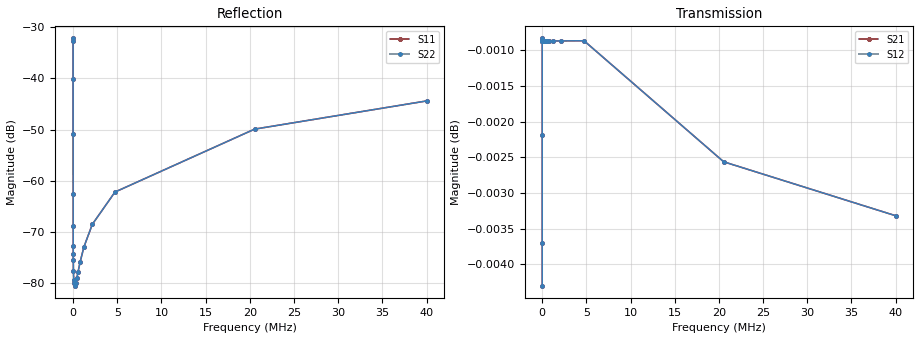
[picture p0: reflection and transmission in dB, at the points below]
!  *** S-Parameter ***
!  Copyright (C) Panasonic Industry
!  Conductive Polymer Aluminum Solid Capacitors (OS-CON)
!  Parts No. 2R5SVT680MX
! Touchstone file from project
# GHZ S RI R 50.000000
! Modal data exported
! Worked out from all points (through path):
!   450 points, 100 Hz to 40 MHz, reference 50 ohm
!   highest |S21| = 0.00 dB at 421.7 kHz (marker M1); lowest = 0.0 dB at 100 Hz (marker M2)
!   lowest |S11| = -80.6 dB at 167.9 kHz (marker M3), VSWR 1.00, Z = 50 + j0.000711 ohm
!   |S11| at or under -10 dB: start of sweep to end of sweep
!   |S22| runs from -80.6 to -32.1 dB; largest |S21 - S12| = 1e-12
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1e-07  0.000818 -0.0247  0.9992 0.0247  0.9992 0.0247  0.000818 -0.0247
1.059254e-07  0.000748 -0.0234  0.9993 0.0234  0.9993 0.0234  0.000748 -0.0234
2.511886e-07  0.000263 -0.00989  0.9997 0.00989  0.9997 0.00989  0.000263 -0.00989
8.659643e-07  0.000135 -0.00288  0.9999 0.00288  0.9999 0.00288  0.000135 -0.00288
3.447466e-06  0.000119 -0.000726  0.9999 0.000726  0.9999 0.000726  0.000119 -0.000726
7.498942e-06  0.000116 -0.000337  0.9999 0.000337  0.9999 0.000337  0.000116 -0.000337
1.295687e-05  0.000114 -0.000198  0.9999 0.000198  0.9999 0.000198  0.000114 -0.000198
1.678804e-05  0.000112 -0.000155  0.9999 0.000155  0.9999 0.000155  0.000112 -0.000155
2.113489e-05  0.000111 -0.000124  0.9999 0.000124  0.9999 0.000124  0.000111 -0.000124
3.548134e-05  0.000106 -7.58e-05  0.9999 7.58e-05  0.9999 7.58e-05  0.000106 -7.58e-05
6.493816e-05  9.97e-05 -3.87e-05  0.9999 3.87e-05  0.9999 3.87e-05  9.97e-05 -3.87e-05
8.912509e-05  9.68e-05 -2.28e-05  0.9999 2.28e-05  0.9999 2.28e-05  9.68e-05 -2.28e-05
0.0001678804  9.32e-05 7.11e-06  0.9999 -7.11e-06  0.9999 -7.11e-06  9.32e-05 7.11e-06
0.0002985383  9.21e-05 3.83e-05  0.9999 -3.83e-05  0.9999 -3.83e-05  9.21e-05 3.83e-05
0.0004216965  9.21e-05 6.27e-05  0.9999 -6.27e-05  0.9999 -6.27e-05  9.21e-05 6.27e-05
0.0005463865  9.25e-05 8.57e-05  0.9999 -8.57e-05  0.9999 -8.57e-05  9.25e-05 8.57e-05
0.0007943282  9.37e-05 0.000129  0.9999 -0.000129  0.9999 -0.000129  9.37e-05 0.000129
0.001223207  9.67e-05 0.000202  0.9999 -0.000202  0.9999 -0.000202  9.67e-05 0.000202
0.002175204  0.000105 0.000358  0.9999 -0.000358  0.9999 -0.000358  0.000105 0.000358
0.004731513  0.000123 0.000762  0.9999 -0.000762  0.9999 -0.000762  0.000123 0.000762
0.02053525  0.000261 0.00318  0.9997 -0.00318  0.9997 -0.00318  0.000261 0.00318
0.04  0.000436 0.00601  0.9996 -0.00601  0.9996 -0.00601  0.000436 0.00601
